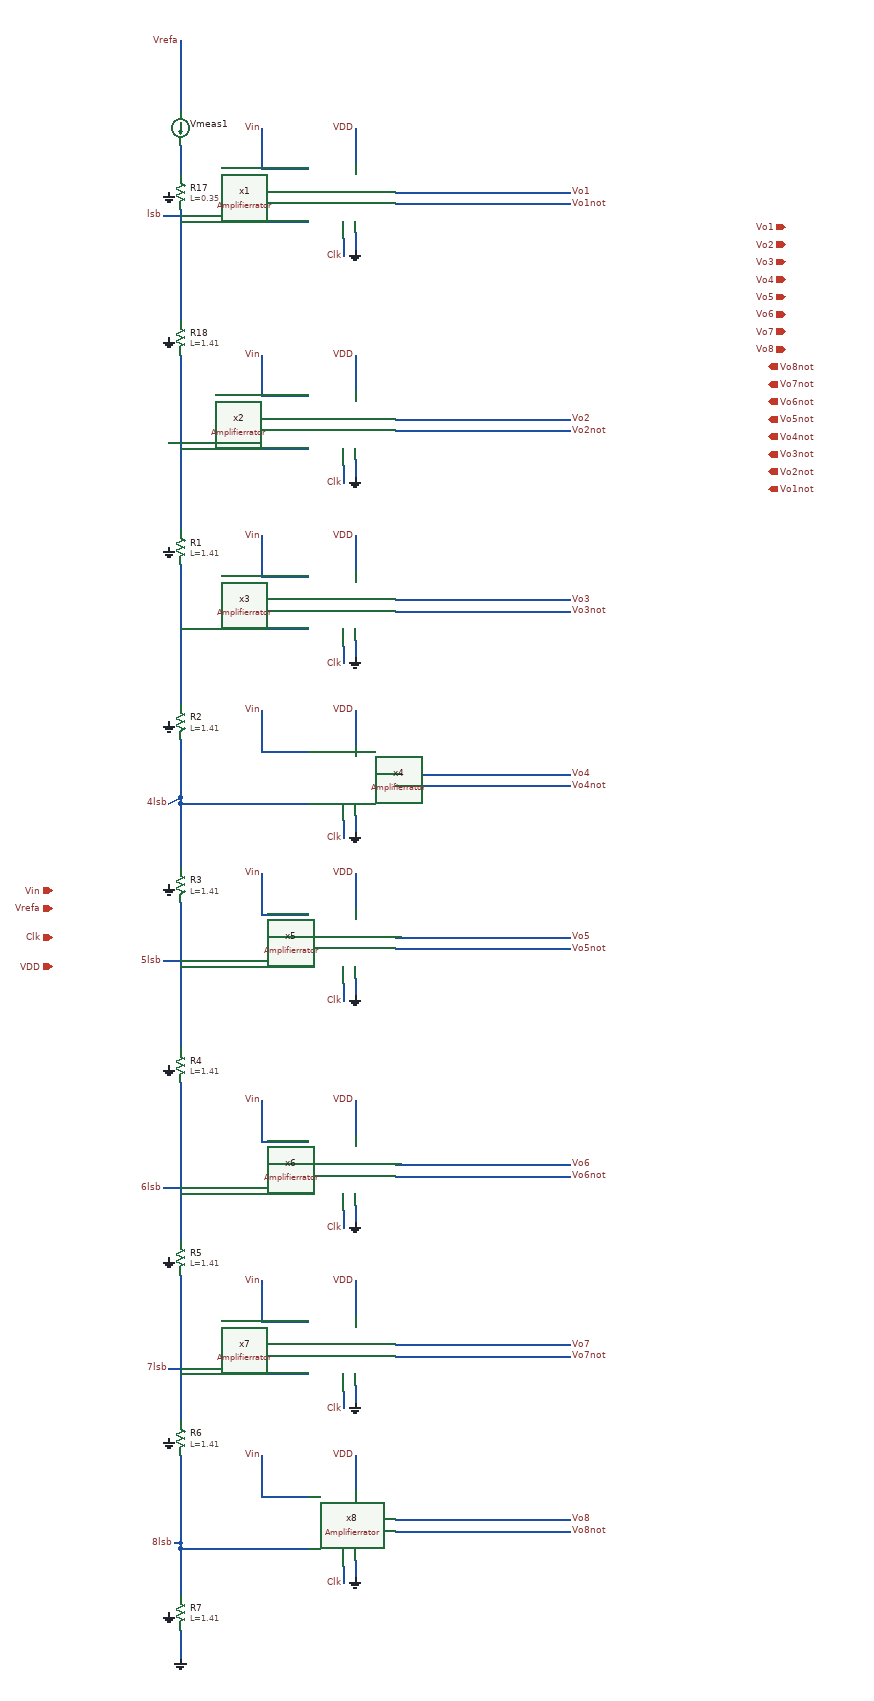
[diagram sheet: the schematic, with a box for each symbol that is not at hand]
v {xschem version=3.4.6 file_version=1.2}
G {}
K {}
V {}
S {}
E {}
N -90 -200 -90 -160 {
lab=5lsb}
N -90 -180 130 -180 {
lab=5lsb}
N -90 190 -90 230 {
lab=6lsb}
N -90 210 130 210 {
lab=6lsb}
N -90 500 -90 540 {
lab=7lsb}
N -90 520 130 520 {
lab=7lsb}
N -90 350 -90 440 {
lab=7lsb}
N -90 660 -90 740 {
lab=8lsb}
N -90 820 130 820 {
lab=8lsb}
N -90 -1480 -90 -1440 {
lab=lsb}
N -90 -1460 130 -1460 {
lab=lsb}
N -90 -1230 -90 -1050 {
lab=#net1}
N -90 -1070 130 -1070 {
lab=#net1}
N -90 -990 -90 -930 {
lab=#net1}
N -90 -870 -90 -740 {
lab=#net2}
N -90 -760 130 -760 {
lab=#net2}
N -90 -460 130 -460 {
lab=4lsb}
N -90 -1770 -90 -1650 {
lab=Vrefa}
N 290 470 580 470 {
lab=Vo7}
N 280 160 580 160 {
lab=Vo6}
N 280 -230 580 -230 {
lab=Vo5}
N 280 -510 580 -510 {
lab=Vo4}
N 290 -810 580 -810 {
lab=Vo3}
N 280 -1120 580 -1120 {
lab=Vo2}
N 280 -1510 580 -1510 {
lab=Vo1}
N 50 -1550 130 -1550 {
lab=Vin}
N 50 -1620 50 -1550 {
lab=Vin}
N 210 -1620 210 -1580 {
lab=VDD}
N 210 -1440 210 -1410 {
lab=GND}
N 210 -1580 210 -1560 {
lab=VDD}
N 190 -1430 190 -1400 {
lab=Clk}
N 50 -1160 130 -1160 {
lab=Vin}
N 50 -1230 50 -1160 {
lab=Vin}
N 210 -1230 210 -1190 {
lab=VDD}
N 210 -1050 210 -1020 {
lab=GND}
N 210 -1190 210 -1170 {
lab=VDD}
N 190 -1040 190 -1010 {
lab=Clk}
N 50 -850 130 -850 {
lab=Vin}
N 50 -920 50 -850 {
lab=Vin}
N 210 -920 210 -880 {
lab=VDD}
N 210 -740 210 -710 {
lab=GND}
N 210 -880 210 -860 {
lab=VDD}
N 190 -730 190 -700 {
lab=Clk}
N 280 -810 290 -810 {
lab=Vo3}
N 50 -550 130 -550 {
lab=Vin}
N 50 -620 50 -550 {
lab=Vin}
N 210 -620 210 -580 {
lab=VDD}
N 210 -440 210 -410 {
lab=GND}
N 210 -580 210 -560 {
lab=VDD}
N 190 -430 190 -400 {
lab=Clk}
N 280 -510 290 -510 {
lab=Vo4}
N 50 -270 130 -270 {
lab=Vin}
N 50 -340 50 -270 {
lab=Vin}
N 210 -340 210 -300 {
lab=VDD}
N 210 -160 210 -130 {
lab=GND}
N 210 -300 210 -280 {
lab=VDD}
N 190 -150 190 -120 {
lab=Clk}
N 280 -230 290 -230 {
lab=Vo5}
N 50 120 130 120 {
lab=Vin}
N 50 50 50 120 {
lab=Vin}
N 210 50 210 90 {
lab=VDD}
N 210 230 210 260 {
lab=GND}
N 210 90 210 110 {
lab=VDD}
N 190 240 190 270 {
lab=Clk}
N 280 160 290 160 {
lab=Vo6}
N 50 430 130 430 {
lab=Vin}
N 50 360 50 430 {
lab=Vin}
N 210 360 210 400 {
lab=VDD}
N 210 540 210 570 {
lab=GND}
N 210 400 210 420 {
lab=VDD}
N 190 550 190 580 {
lab=Clk}
N 280 470 290 470 {
lab=Vo7}
N 50 730 130 730 {
lab=Vin}
N 50 660 50 730 {
lab=Vin}
N 210 660 210 700 {
lab=VDD}
N 210 840 210 870 {
lab=GND}
N 210 700 210 720 {
lab=VDD}
N 190 850 190 880 {
lab=Clk}
N 280 770 290 770 {
lab=Vo8}
N 280 -1490 580 -1490 {
lab=Vo1not}
N 280 -1100 580 -1100 {
lab=Vo2not}
N 280 -790 580 -790 {
lab=Vo3not}
N 280 -490 580 -490 {
lab=Vo4not}
N 280 -210 580 -210 {
lab=Vo5not}
N 280 180 580 180 {
lab=Vo6not}
N 280 490 580 490 {
lab=Vo7not}
N 280 790 580 790 {
lab=Vo8not}
N -100 810 -90 810 {
lab=8lsb}
N -110 510 -90 510 {
lab=7lsb}
N -120 200 -90 200 {
lab=6lsb}
N -120 -190 -90 -190 {
lab=5lsb}
N -110 -460 -90 -470 {
lab=4lsb}
N -110 -1080 -90 -1080 {
lab=#net1}
N -120 -1470 -90 -1470 {
lab=lsb}
N 290 770 580 770 {
lab=Vo8}
N -90 -1440 -90 -1380 {
lab=lsb}
N -90 -1050 -90 -1000 {
lab=#net1}
N -90 -1000 -90 -990 {
lab=#net1}
N -90 -440 -90 -350 {
lab=4lsb}
N -90 -160 -90 -100 {
lab=5lsb}
N -90 230 -90 290 {
lab=6lsb}
N -90 540 -90 600 {
lab=7lsb}
N -90 840 -90 900 {
lab=8lsb}
N -90 -1380 -90 -1290 {
lab=lsb}
N -90 -690 -90 -630 {
lab=#net2}
N -90 -570 -90 -470 {
lab=4lsb}
N -90 -470 -90 -460 {
lab=4lsb}
N -90 -460 -90 -440 {
lab=4lsb}
N -90 -290 -90 -200 {
lab=5lsb}
N -90 130 -90 190 {
lab=6lsb}
N -90 60 -90 130 {
lab=6lsb}
N -90 440 -90 500 {
lab=7lsb}
N -90 740 -90 790 {
lab=8lsb}
N -90 790 -90 810 {
lab=8lsb}
N -90 810 -90 820 {
lab=8lsb}
N -90 820 -90 840 {
lab=8lsb}
N -90 20 -90 60 {
lab=6lsb}
N -90 -100 -90 -40 {
lab=5lsb}
N -90 -740 -90 -690 {
lab=#net2}
N -90 -1590 -90 -1540 {
lab=#net3}
N -90 960 -90 1010 {lab=GND}
C {devices/lab_pin.sym} -90 -1770 1 0 {name=p19 sig_type=std_logic lab=Vrefa}
C {devices/ammeter.sym} -90 -1620 0 0 {name=Vmeas1 savecurrent=true}
C {devices/ipin.sym} -310 -310 0 0 {name=p26 lab=Vin}
C {devices/ipin.sym} -310 -280 0 0 {name=p27 lab=Vrefa}
C {devices/ipin.sym} -310 -230 0 0 {name=p28 lab=Clk}
C {devices/ipin.sym} -310 -180 0 0 {name=p29 lab=VDD}
C {devices/lab_pin.sym} 50 -1620 1 0 {name=p57 lab=Vin
}
C {devices/lab_pin.sym} 210 -1620 1 0 {name=p58 sig_type=std_logic lab=VDD}
C {devices/gnd.sym} 210 -1410 0 0 {name=l17 lab=GND}
C {devices/lab_pin.sym} 190 -1400 0 0 {name=p59 sig_type=std_logic lab=Clk}
C {devices/lab_pin.sym} 50 -1230 1 0 {name=p4 lab=Vin
}
C {devices/lab_pin.sym} 210 -1230 1 0 {name=p7 sig_type=std_logic lab=VDD}
C {devices/gnd.sym} 210 -1020 0 0 {name=l1 lab=GND}
C {devices/lab_pin.sym} 190 -1010 0 0 {name=p8 sig_type=std_logic lab=Clk}
C {devices/lab_pin.sym} 50 -920 1 0 {name=p9 lab=Vin
}
C {devices/lab_pin.sym} 210 -920 1 0 {name=p10 sig_type=std_logic lab=VDD}
C {devices/gnd.sym} 210 -710 0 0 {name=l2 lab=GND}
C {devices/lab_pin.sym} 190 -700 0 0 {name=p11 sig_type=std_logic lab=Clk}
C {devices/lab_pin.sym} 50 -620 1 0 {name=p12 lab=Vin
}
C {devices/lab_pin.sym} 210 -620 1 0 {name=p13 sig_type=std_logic lab=VDD}
C {devices/gnd.sym} 210 -410 0 0 {name=l3 lab=GND}
C {devices/lab_pin.sym} 190 -400 0 0 {name=p14 sig_type=std_logic lab=Clk}
C {devices/lab_pin.sym} 50 -340 1 0 {name=p15 lab=Vin
}
C {devices/lab_pin.sym} 210 -340 1 0 {name=p16 sig_type=std_logic lab=VDD}
C {devices/gnd.sym} 210 -130 0 0 {name=l4 lab=GND}
C {devices/lab_pin.sym} 190 -120 0 0 {name=p17 sig_type=std_logic lab=Clk}
C {devices/lab_pin.sym} 50 50 1 0 {name=p18 lab=Vin
}
C {devices/lab_pin.sym} 210 50 1 0 {name=p24 sig_type=std_logic lab=VDD}
C {devices/gnd.sym} 210 260 0 0 {name=l5 lab=GND}
C {devices/lab_pin.sym} 190 270 0 0 {name=p25 sig_type=std_logic lab=Clk}
C {devices/lab_pin.sym} 50 360 1 0 {name=p39 lab=Vin
}
C {devices/lab_pin.sym} 210 360 1 0 {name=p40 sig_type=std_logic lab=VDD}
C {devices/gnd.sym} 210 570 0 0 {name=l6 lab=GND}
C {devices/lab_pin.sym} 190 580 0 0 {name=p41 sig_type=std_logic lab=Clk}
C {devices/lab_pin.sym} 50 660 1 0 {name=p45 lab=Vin
}
C {devices/lab_pin.sym} 210 660 1 0 {name=p46 sig_type=std_logic lab=VDD}
C {devices/gnd.sym} 210 870 0 0 {name=l8 lab=GND}
C {devices/lab_pin.sym} 190 880 0 0 {name=p47 sig_type=std_logic lab=Clk}
C {devices/lab_pin.sym} 580 -1510 2 0 {name=p86 sig_type=std_logic lab=Vo1}
C {devices/lab_pin.sym} 580 -1490 2 0 {name=p91 sig_type=std_logic lab=Vo1not}
C {devices/lab_pin.sym} 580 -1120 2 0 {name=p92 sig_type=std_logic lab=Vo2}
C {devices/lab_pin.sym} 580 -1100 2 0 {name=p93 sig_type=std_logic lab=Vo2not}
C {devices/lab_pin.sym} 580 -810 2 0 {name=p94 sig_type=std_logic lab=Vo3}
C {devices/lab_pin.sym} 580 -790 2 0 {name=p95 sig_type=std_logic lab=Vo3not}
C {devices/lab_pin.sym} 580 -510 2 0 {name=p96 sig_type=std_logic lab=Vo4}
C {devices/lab_pin.sym} 580 -490 2 0 {name=p97 sig_type=std_logic lab=Vo4not}
C {devices/lab_pin.sym} 580 -230 2 0 {name=p98 sig_type=std_logic lab=Vo5}
C {devices/lab_pin.sym} 580 -210 2 0 {name=p99 sig_type=std_logic lab=Vo5not}
C {devices/lab_pin.sym} 580 160 2 0 {name=p100 sig_type=std_logic lab=Vo6}
C {devices/lab_pin.sym} 580 180 2 0 {name=p101 sig_type=std_logic lab=Vo6not}
C {devices/lab_pin.sym} 580 470 2 0 {name=p102 sig_type=std_logic lab=Vo7}
C {devices/lab_pin.sym} 580 490 2 0 {name=p103 sig_type=std_logic lab=Vo7not}
C {devices/lab_pin.sym} 580 770 2 0 {name=p104 sig_type=std_logic lab=Vo8}
C {devices/lab_pin.sym} 580 790 2 0 {name=p105 sig_type=std_logic lab=Vo8not}
C {devices/lab_pin.sym} -100 810 0 0 {name=p126 sig_type=std_logic lab=8lsb}
C {devices/lab_pin.sym} -110 510 0 0 {name=p127 sig_type=std_logic lab=7lsb}
C {devices/lab_pin.sym} -120 200 0 0 {name=p128 sig_type=std_logic lab=6lsb}
C {devices/lab_pin.sym} -120 -190 0 0 {name=p129 sig_type=std_logic lab=5lsb}
C {devices/lab_pin.sym} -110 -460 0 0 {name=p130 sig_type=std_logic lab=4lsb}
C {devices/lab_pin.sym} -120 -1470 0 0 {name=p133 sig_type=std_logic lab=lsb}
C {xschem/userLib/Amplifierrator.sym} 280 -1470 0 0 {name=x1}
C {xschem/userLib/Amplifierrator.sym} 280 -1080 0 0 {name=x2}
C {xschem/userLib/Amplifierrator.sym} 280 -770 0 0 {name=x3}
C {xschem/userLib/Amplifierrator.sym} 280 -470 0 0 {name=x4}
C {xschem/userLib/Amplifierrator.sym} 280 -190 0 0 {name=x5}
C {xschem/userLib/Amplifierrator.sym} 280 200 0 0 {name=x6}
C {xschem/userLib/Amplifierrator.sym} 280 510 0 0 {name=x7}
C {xschem/userLib/Amplifierrator.sym} 280 810 0 0 {name=x8}
C {devices/gnd.sym} -110 -1510 1 0 {name=l19 lab=GND}
C {devices/gnd.sym} -110 -1260 1 0 {name=l20 lab=GND}
C {devices/gnd.sym} -110 -900 1 0 {name=l21 lab=GND}
C {devices/gnd.sym} -110 -600 1 0 {name=l22 lab=GND}
C {devices/gnd.sym} -110 -320 1 0 {name=l23 lab=GND}
C {devices/gnd.sym} -110 -10 1 0 {name=l24 lab=GND}
C {devices/gnd.sym} -110 320 1 0 {name=l25 lab=GND}
C {devices/gnd.sym} -110 630 1 0 {name=l26 lab=GND}
C {devices/gnd.sym} -110 930 1 0 {name=l27 lab=GND}
C {sky130_fd_pr/res_high_po_1p41.sym} -90 -1260 0 0 {name=R18
L=1.41
model=res_high_po_1p41
spiceprefix=X
mult=4}
C {sky130_fd_pr/res_high_po_1p41.sym} -90 -900 0 0 {name=R1
L=1.41
model=res_high_po_1p41
spiceprefix=X
mult=4}
C {sky130_fd_pr/res_high_po_1p41.sym} -90 -600 0 0 {name=R2
L=1.41
model=res_high_po_1p41
spiceprefix=X
mult=4}
C {sky130_fd_pr/res_high_po_1p41.sym} -90 -320 0 0 {name=R3
L=1.41
model=res_high_po_1p41
spiceprefix=X
mult=4}
C {sky130_fd_pr/res_high_po_1p41.sym} -90 -10 0 0 {name=R4
L=1.41
model=res_high_po_1p41
spiceprefix=X
mult=4}
C {sky130_fd_pr/res_high_po_1p41.sym} -90 320 0 0 {name=R5
L=1.41
model=res_high_po_1p41
spiceprefix=X
mult=4}
C {sky130_fd_pr/res_high_po_1p41.sym} -90 630 0 0 {name=R6
L=1.41
model=res_high_po_1p41
spiceprefix=X
mult=4}
C {sky130_fd_pr/res_high_po_1p41.sym} -90 930 0 0 {name=R7
L=1.41
model=res_high_po_1p41
spiceprefix=X
mult=4}
C {sky130_fd_pr/res_high_po_0p35.sym} -90 -1510 0 0 {name=R17
L=0.35
model=res_high_po_0p35
spiceprefix=X
mult=1}
C {devices/gnd.sym} -90 1010 0 0 {name=l7 lab=GND}
C {devices/iopin.sym} 950 -1450 0 0 {name=p1 lab=Vo1}
C {devices/iopin.sym} 950 -1420 0 0 {name=p2 lab=Vo2}
C {devices/iopin.sym} 950 -1390 0 0 {name=p5 lab=Vo3}
C {devices/iopin.sym} 950 -1360 0 0 {name=p6 lab=Vo4}
C {devices/iopin.sym} 950 -1330 0 0 {name=p31 lab=Vo5}
C {devices/iopin.sym} 950 -1300 0 0 {name=p32 lab=Vo6}
C {devices/iopin.sym} 950 -1270 0 0 {name=p33 lab=Vo7}
C {devices/iopin.sym} 950 -1240 0 0 {name=p34 lab=Vo8}
C {devices/iopin.sym} 920 -1210 2 1 {name=p82 lab=Vo8not}
C {devices/iopin.sym} 920 -1180 2 1 {name=p83 lab=Vo7not}
C {devices/iopin.sym} 920 -1150 2 1 {name=p84 lab=Vo6not}
C {devices/iopin.sym} 920 -1120 2 1 {name=p85 lab=Vo5not}
C {devices/iopin.sym} 920 -1090 2 1 {name=p87 lab=Vo4not}
C {devices/iopin.sym} 920 -1060 2 1 {name=p88 lab=Vo3not}
C {devices/iopin.sym} 920 -1030 2 1 {name=p89 lab=Vo2not}
C {devices/iopin.sym} 920 -1000 2 1 {name=p90 lab=Vo1not}
